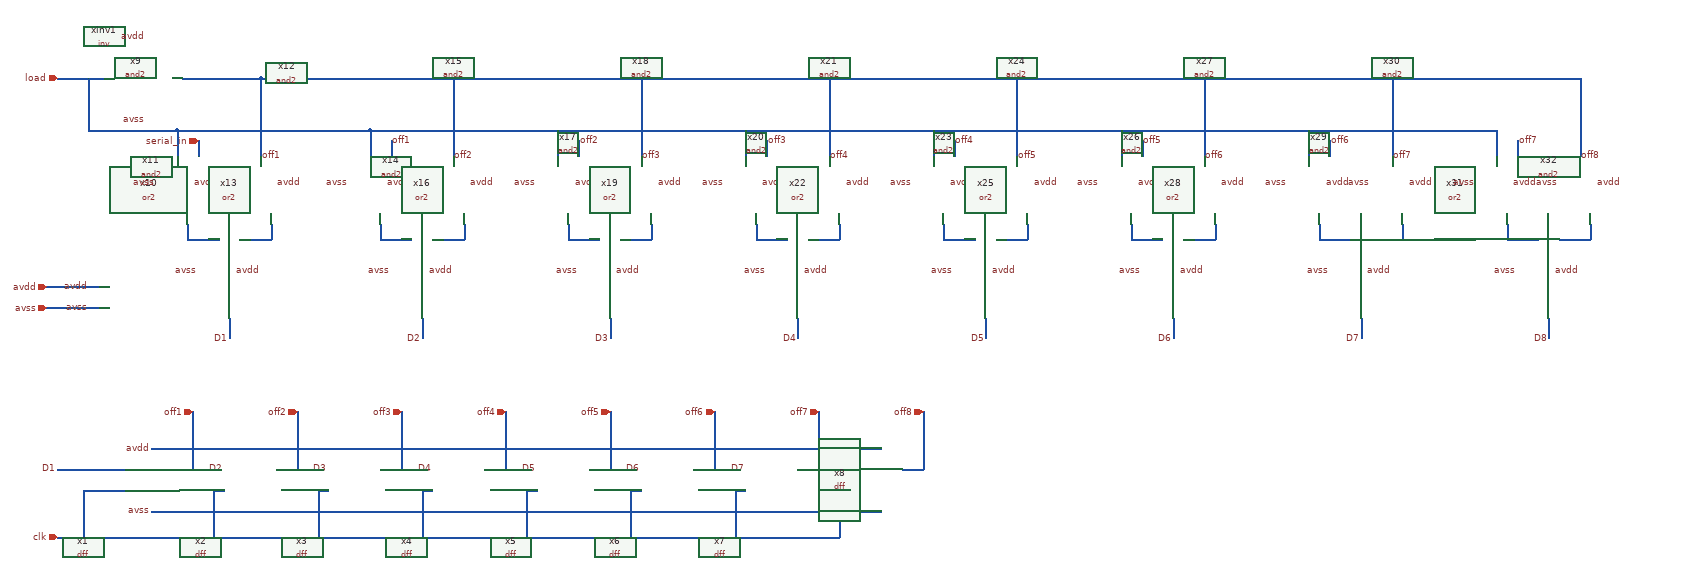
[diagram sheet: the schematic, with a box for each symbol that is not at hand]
v {xschem version=3.4.7 file_version=1.2}
G {}
K {}
V {}
S {}
E {}
N 40 -760 90 -760 {lab=avdd}
N 40 -720 100 -720 {lab=avss}
N 100 -720 140 -720 {lab=avss}
N 90 -760 140 -760 {lab=avdd}
N 240 -450 1440 -450 {lab=avdd}
N 240 -330 1440 -330 {lab=avss}
N 1440 -450 1640 -450 {lab=avdd}
N 1440 -330 1640 -330 {lab=avss}
N 290 -410 320 -410 {lab=off1}
N 480 -410 510 -410 {lab=off2}
N 680 -410 710 -410 {lab=off3}
N 880 -410 910 -410 {lab=off4}
N 1080 -410 1110 -410 {lab=off5}
N 1280 -410 1310 -410 {lab=off6}
N 1480 -410 1510 -410 {lab=off7}
N 320 -520 320 -410 {lab=off1}
N 720 -520 720 -410 {lab=off3}
N 520 -520 520 -410 {lab=off2}
N 920 -520 920 -410 {lab=off4}
N 1120 -520 1120 -410 {lab=off5}
N 1320 -520 1320 -410 {lab=off6}
N 1520 -520 1520 -410 {lab=off7}
N 1680 -410 1710 -410 {lab=off8}
N 60 -410 180 -410 {lab=D1}
N 110 -370 190 -370 {lab=clk}
N 60 -280 100 -280 {lab=clk}
N 100 -280 1540 -280 {lab=clk}
N 300 -1160 450 -1160 {lab=#net1}
N 450 -1160 450 -1010 {lab=#net1}
N 60 -1160 150 -1160 {lab=load}
N 120 -1060 290 -1060 {lab=load}
N 330 -1040 330 -1010 {lab=serial_in}
N 310 -880 310 -850 {lab=#net2}
N 310 -850 370 -850 {lab=#net2}
N 470 -880 470 -850 {lab=#net3}
N 410 -850 470 -850 {lab=#net3}
N 390 -700 390 -660 {lab=D1}
N 290 -1060 290 -1010 {lab=load}
N 120 -1160 120 -1060 {lab=load}
N 820 -1160 820 -1010 {lab=#net1}
N 700 -1040 700 -1010 {lab=off1}
N 680 -880 680 -850 {lab=#net4}
N 680 -850 740 -850 {lab=#net4}
N 840 -880 840 -850 {lab=#net5}
N 780 -850 840 -850 {lab=#net5}
N 760 -700 760 -660 {lab=D2}
N 660 -1060 660 -1010 {lab=load}
N 290 -1060 660 -1060 {lab=load}
N 1180 -1160 1180 -1010 {lab=#net1}
N 1060 -1040 1060 -1010 {lab=off2}
N 1040 -880 1040 -850 {lab=#net6}
N 1040 -850 1100 -850 {lab=#net6}
N 1200 -880 1200 -850 {lab=#net7}
N 1140 -850 1200 -850 {lab=#net7}
N 1120 -700 1120 -660 {lab=D3}
N 1020 -1060 1020 -1010 {lab=load}
N 1540 -1160 1540 -1010 {lab=#net1}
N 1420 -1040 1420 -1010 {lab=off3}
N 1400 -880 1400 -850 {lab=#net8}
N 1400 -850 1460 -850 {lab=#net8}
N 1560 -880 1560 -850 {lab=#net9}
N 1500 -850 1560 -850 {lab=#net9}
N 1480 -700 1480 -660 {lab=D4}
N 1380 -1060 1380 -1010 {lab=load}
N 1900 -1160 1900 -1010 {lab=#net1}
N 1780 -1040 1780 -1010 {lab=off4}
N 1760 -880 1760 -850 {lab=#net10}
N 1760 -850 1820 -850 {lab=#net10}
N 1920 -880 1920 -850 {lab=#net11}
N 1860 -850 1920 -850 {lab=#net11}
N 1840 -700 1840 -660 {lab=D5}
N 1740 -1060 1740 -1010 {lab=load}
N 2260 -1160 2260 -1010 {lab=#net1}
N 2140 -1040 2140 -1010 {lab=off5}
N 2120 -880 2120 -850 {lab=#net12}
N 2120 -850 2180 -850 {lab=#net12}
N 2280 -880 2280 -850 {lab=#net13}
N 2220 -850 2280 -850 {lab=#net13}
N 2200 -700 2200 -660 {lab=D6}
N 2100 -1060 2100 -1010 {lab=load}
N 2620 -1160 2620 -1010 {lab=#net1}
N 2500 -1040 2500 -1010 {lab=off6}
N 2480 -880 2480 -850 {lab=#net14}
N 2480 -850 2540 -850 {lab=#net14}
N 2640 -880 2640 -850 {lab=#net15}
N 2580 -850 2640 -850 {lab=#net15}
N 2560 -700 2560 -660 {lab=D7}
N 2460 -1060 2460 -1010 {lab=load}
N 2980 -1160 2980 -1010 {lab=#net1}
N 2860 -1040 2860 -1010 {lab=off7}
N 2840 -880 2840 -850 {lab=#net16}
N 2840 -850 2900 -850 {lab=#net16}
N 3000 -880 3000 -850 {lab=#net17}
N 2940 -850 3000 -850 {lab=#net17}
N 2920 -700 2920 -660 {lab=D8}
N 2820 -1060 2820 -1010 {lab=load}
N 660 -1060 2820 -1060 {lab=load}
N 450 -1160 2980 -1160 {lab=#net1}
N 180 -410 190 -410 {lab=D1}
N 110 -370 110 -280 {lab=clk}
N 360 -370 380 -370 {lab=clk}
N 360 -370 360 -280 {lab=clk}
N 560 -370 580 -370 {lab=clk}
N 560 -370 560 -280 {lab=clk}
N 760 -370 780 -370 {lab=clk}
N 760 -370 760 -280 {lab=clk}
N 960 -370 980 -370 {lab=clk}
N 960 -370 960 -280 {lab=clk}
N 1160 -370 1180 -370 {lab=clk}
N 1160 -370 1160 -280 {lab=clk}
N 1360 -370 1380 -370 {lab=clk}
N 1360 -370 1360 -280 {lab=clk}
N 1560 -370 1580 -370 {lab=clk}
N 1560 -370 1560 -280 {lab=clk}
N 1540 -280 1560 -280 {lab=clk}
N 1510 -410 1520 -410 {lab=off7}
N 1710 -410 1720 -410 {lab=off8}
N 1720 -520 1720 -410 {lab=off8}
N 1310 -410 1320 -410 {lab=off6}
N 1110 -410 1120 -410 {lab=off5}
N 910 -410 920 -410 {lab=off4}
N 710 -410 720 -410 {lab=off3}
N 510 -410 520 -410 {lab=off2}
C {iopin.sym} 40 -760 2 0 {name=p9 lab=avdd}
C {iopin.sym} 40 -720 2 0 {name=p10 lab=avss}
C {lab_wire.sym} 120 -760 0 0 {name=p13 sig_type=std_logic lab=avdd}
C {lab_wire.sym} 120 -720 0 0 {name=p14 sig_type=std_logic lab=avss}
C {lab_wire.sym} 240 -450 0 0 {name=p1 sig_type=std_logic lab=avdd}
C {lab_wire.sym} 240 -330 2 1 {name=p2 sig_type=std_logic lab=avss}
C {iopin.sym} 320 -520 2 0 {name=p3 lab=off1}
C {iopin.sym} 520 -520 2 0 {name=p4 lab=off2}
C {iopin.sym} 720 -520 2 0 {name=p5 lab=off3}
C {iopin.sym} 920 -520 2 0 {name=p6 lab=off4}
C {iopin.sym} 1120 -520 2 0 {name=p7 lab=off5}
C {iopin.sym} 1320 -520 2 0 {name=p8 lab=off6}
C {iopin.sym} 1520 -520 2 0 {name=p11 lab=off7}
C {iopin.sym} 1720 -520 2 0 {name=p12 lab=off8}
C {iopin.sym} 330 -1040 2 0 {name=p15 lab=serial_in}
C {iopin.sym} 60 -280 2 0 {name=p16 lab=clk}
C {libs/SIPO/and2.sym} 130 -1170 1 0 {name=x9}
C {libs/SIPO/or2.sym} 170 -960 1 0 {name=x10}
C {comparator/inv.sym} 150 -1240 0 0 {name=xinv1}
C {libs/SIPO/and2.sym} 290 -1170 1 0 {name=x11}
C {lab_wire.sym} 370 -960 3 1 {name=p17 sig_type=std_logic lab=avdd}
C {lab_wire.sym} 530 -960 3 1 {name=p18 sig_type=std_logic lab=avdd}
C {lab_wire.sym} 250 -960 1 0 {name=p19 sig_type=std_logic lab=avss}
C {lab_wire.sym} 410 -960 1 0 {name=p20 sig_type=std_logic lab=avss}
C {lab_wire.sym} 330 -790 1 0 {name=p21 sig_type=std_logic lab=avss}
C {lab_wire.sym} 450 -790 3 1 {name=p22 sig_type=std_logic lab=avdd}
C {lab_wire.sym} 230 -1080 0 0 {name=p23 sig_type=std_logic lab=avss}
C {lab_wire.sym} 230 -1240 2 1 {name=p24 sig_type=std_logic lab=avdd}
C {iopin.sym} 60 -1160 2 0 {name=p25 lab=load}
C {lab_wire.sym} 390 -660 0 0 {name=p26 sig_type=std_logic lab=D1}
C {lab_wire.sym} 60 -410 0 0 {name=p27 sig_type=std_logic lab=D1}
C {lab_wire.sym} 490 -1010 1 0 {name=p28 sig_type=std_logic lab=off1}
C {libs/SIPO/and2.sym} 500 -1170 1 0 {name=x12}
C {libs/SIPO/or2.sym} 540 -960 1 0 {name=x13}
C {libs/SIPO/and2.sym} 660 -1170 1 0 {name=x14}
C {lab_wire.sym} 740 -960 3 1 {name=p30 sig_type=std_logic lab=avdd}
C {lab_wire.sym} 620 -960 1 0 {name=p31 sig_type=std_logic lab=avss}
C {lab_wire.sym} 780 -960 1 0 {name=p32 sig_type=std_logic lab=avss}
C {lab_wire.sym} 700 -790 1 0 {name=p33 sig_type=std_logic lab=avss}
C {lab_wire.sym} 820 -790 3 1 {name=p34 sig_type=std_logic lab=avdd}
C {lab_wire.sym} 760 -660 0 0 {name=p35 sig_type=std_logic lab=D2}
C {lab_wire.sym} 860 -1010 1 0 {name=p36 sig_type=std_logic lab=off2}
C {lab_wire.sym} 700 -1040 2 0 {name=p29 sig_type=std_logic lab=off1}
C {lab_wire.sym} 380 -410 0 0 {name=p37 sig_type=std_logic lab=D2}
C {lab_wire.sym} 580 -410 0 0 {name=p38 sig_type=std_logic lab=D3}
C {lab_wire.sym} 780 -410 0 0 {name=p39 sig_type=std_logic lab=D4}
C {lab_wire.sym} 980 -410 0 0 {name=p40 sig_type=std_logic lab=D5}
C {lab_wire.sym} 1180 -410 0 0 {name=p41 sig_type=std_logic lab=D6}
C {lab_wire.sym} 1380 -410 0 0 {name=p42 sig_type=std_logic lab=D7}
C {lab_wire.sym} 1580 -410 0 0 {name=p43 sig_type=std_logic lab=D8}
C {libs/SIPO/and2.sym} 860 -1170 1 0 {name=x15}
C {libs/SIPO/or2.sym} 900 -960 1 0 {name=x16}
C {libs/SIPO/and2.sym} 1020 -1170 1 0 {name=x17}
C {lab_wire.sym} 1100 -960 3 1 {name=p44 sig_type=std_logic lab=avdd}
C {lab_wire.sym} 980 -960 1 0 {name=p45 sig_type=std_logic lab=avss}
C {lab_wire.sym} 1140 -960 1 0 {name=p46 sig_type=std_logic lab=avss}
C {lab_wire.sym} 1060 -790 1 0 {name=p47 sig_type=std_logic lab=avss}
C {lab_wire.sym} 1180 -790 3 1 {name=p48 sig_type=std_logic lab=avdd}
C {lab_wire.sym} 1120 -660 0 0 {name=p49 sig_type=std_logic lab=D3}
C {lab_wire.sym} 1220 -1010 1 0 {name=p50 sig_type=std_logic lab=off3}
C {lab_wire.sym} 1060 -1040 2 0 {name=p51 sig_type=std_logic lab=off2}
C {libs/SIPO/and2.sym} 1220 -1170 1 0 {name=x18}
C {libs/SIPO/or2.sym} 1260 -960 1 0 {name=x19}
C {libs/SIPO/and2.sym} 1380 -1170 1 0 {name=x20}
C {lab_wire.sym} 1460 -960 3 1 {name=p52 sig_type=std_logic lab=avdd}
C {lab_wire.sym} 1340 -960 1 0 {name=p53 sig_type=std_logic lab=avss}
C {lab_wire.sym} 1500 -960 1 0 {name=p54 sig_type=std_logic lab=avss}
C {lab_wire.sym} 1420 -790 1 0 {name=p55 sig_type=std_logic lab=avss}
C {lab_wire.sym} 1540 -790 3 1 {name=p56 sig_type=std_logic lab=avdd}
C {lab_wire.sym} 1480 -660 0 0 {name=p57 sig_type=std_logic lab=D4}
C {lab_wire.sym} 1580 -1010 1 0 {name=p58 sig_type=std_logic lab=off4}
C {lab_wire.sym} 1420 -1040 2 0 {name=p59 sig_type=std_logic lab=off3}
C {libs/SIPO/and2.sym} 1580 -1170 1 0 {name=x21}
C {libs/SIPO/or2.sym} 1620 -960 1 0 {name=x22}
C {libs/SIPO/and2.sym} 1740 -1170 1 0 {name=x23}
C {lab_wire.sym} 1820 -960 3 1 {name=p60 sig_type=std_logic lab=avdd}
C {lab_wire.sym} 1700 -960 1 0 {name=p61 sig_type=std_logic lab=avss}
C {lab_wire.sym} 1860 -960 1 0 {name=p62 sig_type=std_logic lab=avss}
C {lab_wire.sym} 1780 -790 1 0 {name=p63 sig_type=std_logic lab=avss}
C {lab_wire.sym} 1900 -790 3 1 {name=p64 sig_type=std_logic lab=avdd}
C {lab_wire.sym} 1840 -660 0 0 {name=p65 sig_type=std_logic lab=D5}
C {lab_wire.sym} 1940 -1010 1 0 {name=p66 sig_type=std_logic lab=off5}
C {lab_wire.sym} 1780 -1040 2 0 {name=p67 sig_type=std_logic lab=off4}
C {libs/SIPO/and2.sym} 1940 -1170 1 0 {name=x24}
C {libs/SIPO/or2.sym} 1980 -960 1 0 {name=x25}
C {libs/SIPO/and2.sym} 2100 -1170 1 0 {name=x26}
C {lab_wire.sym} 2180 -960 3 1 {name=p68 sig_type=std_logic lab=avdd}
C {lab_wire.sym} 2060 -960 1 0 {name=p69 sig_type=std_logic lab=avss}
C {lab_wire.sym} 2220 -960 1 0 {name=p70 sig_type=std_logic lab=avss}
C {lab_wire.sym} 2140 -790 1 0 {name=p71 sig_type=std_logic lab=avss}
C {lab_wire.sym} 2260 -790 3 1 {name=p72 sig_type=std_logic lab=avdd}
C {lab_wire.sym} 2200 -660 0 0 {name=p73 sig_type=std_logic lab=D6}
C {lab_wire.sym} 2300 -1010 1 0 {name=p74 sig_type=std_logic lab=off6}
C {lab_wire.sym} 2140 -1040 2 0 {name=p75 sig_type=std_logic lab=off5}
C {libs/SIPO/and2.sym} 2300 -1170 1 0 {name=x27}
C {libs/SIPO/or2.sym} 2340 -960 1 0 {name=x28}
C {libs/SIPO/and2.sym} 2460 -1170 1 0 {name=x29}
C {lab_wire.sym} 2540 -960 3 1 {name=p76 sig_type=std_logic lab=avdd}
C {lab_wire.sym} 2420 -960 1 0 {name=p77 sig_type=std_logic lab=avss}
C {lab_wire.sym} 2580 -960 1 0 {name=p78 sig_type=std_logic lab=avss}
C {lab_wire.sym} 2500 -790 1 0 {name=p79 sig_type=std_logic lab=avss}
C {lab_wire.sym} 2620 -790 3 1 {name=p80 sig_type=std_logic lab=avdd}
C {lab_wire.sym} 2560 -660 0 0 {name=p81 sig_type=std_logic lab=D7}
C {lab_wire.sym} 2660 -1010 1 0 {name=p82 sig_type=std_logic lab=off7}
C {lab_wire.sym} 2500 -1040 2 0 {name=p83 sig_type=std_logic lab=off6}
C {libs/SIPO/and2.sym} 2660 -1170 1 0 {name=x30}
C {libs/SIPO/or2.sym} 2700 -960 1 0 {name=x31}
C {libs/SIPO/and2.sym} 2820 -1170 1 0 {name=x32}
C {lab_wire.sym} 2900 -960 3 1 {name=p84 sig_type=std_logic lab=avdd}
C {lab_wire.sym} 2780 -960 1 0 {name=p85 sig_type=std_logic lab=avss}
C {lab_wire.sym} 2940 -960 1 0 {name=p86 sig_type=std_logic lab=avss}
C {lab_wire.sym} 2860 -790 1 0 {name=p87 sig_type=std_logic lab=avss}
C {lab_wire.sym} 2980 -790 3 1 {name=p88 sig_type=std_logic lab=avdd}
C {lab_wire.sym} 2920 -660 0 0 {name=p89 sig_type=std_logic lab=D8}
C {lab_wire.sym} 3020 -1010 1 0 {name=p90 sig_type=std_logic lab=off8}
C {lab_wire.sym} 2860 -1040 2 0 {name=p91 sig_type=std_logic lab=off7}
C {libs/SIPO/dff.sym} 90 -280 0 0 {name=x1}
C {libs/SIPO/dff.sym} 280 -280 0 0 {name=x2}
C {libs/SIPO/dff.sym} 480 -280 0 0 {name=x3}
C {libs/SIPO/dff.sym} 680 -280 0 0 {name=x4}
C {libs/SIPO/dff.sym} 880 -280 0 0 {name=x5}
C {libs/SIPO/dff.sym} 1080 -280 0 0 {name=x6}
C {libs/SIPO/dff.sym} 1280 -280 0 0 {name=x7}
C {libs/SIPO/dff.sym} 1480 -280 0 0 {name=x8}
C {lab_wire.sym} 900 -960 3 1 {name=p92 sig_type=std_logic lab=avdd}
C {lab_wire.sym} 1260 -960 3 1 {name=p93 sig_type=std_logic lab=avdd}
C {lab_wire.sym} 1620 -960 3 1 {name=p94 sig_type=std_logic lab=avdd}
C {lab_wire.sym} 1980 -960 3 1 {name=p95 sig_type=std_logic lab=avdd}
C {lab_wire.sym} 2340 -960 3 1 {name=p96 sig_type=std_logic lab=avdd}
C {lab_wire.sym} 2700 -960 3 1 {name=p97 sig_type=std_logic lab=avdd}
C {lab_wire.sym} 3060 -960 3 1 {name=p98 sig_type=std_logic lab=avdd}
